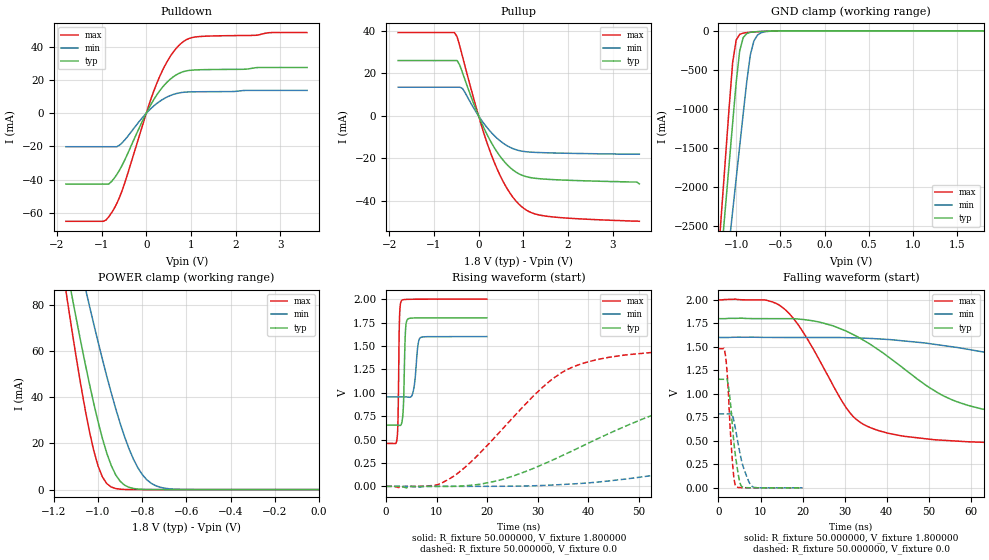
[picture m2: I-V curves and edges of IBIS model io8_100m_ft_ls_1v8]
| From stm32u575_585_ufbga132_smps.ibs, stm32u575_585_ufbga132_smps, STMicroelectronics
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|   Model io8_100m_ft_ls_1v8
[Model]  io8_100m_ft_ls_1v8
Model_type I/O
Polarity   Non-Inverting
Enable   Active-Low
Vinl =   0.540000V
Vinh =   1.260000V
Vmeas =  0.900000V
Cref =   50.000000pF
Rref =   100.000000M
Vref =   0.0V
C_comp   3.148300pF   3.147400pF   3.196500pF
[Temperature Range]   25.000000   0.140000k   -40.000000
[Pullup Reference]   1.800000V   1.600000V   2.000000V
[Pulldown Reference]   0.0V   0.0V   0.0V
[POWER Clamp Reference]   1.800000V   1.600000V   2.000000V
[GND Clamp Reference]   0.0V   0.0V   0.0V
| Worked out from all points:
|   slope of the pulldown table from 0 to 0.27 V, typ, clamps not added: 21.7 ohm
|   slope of the pullup table from 0 to 0.27 V, typ, clamps not added: 22.6 ohm
|   GND clamp passes 1 mA (typ) near -0.51 V on its own axis
|   POWER clamp passes 1 mA (typ) near -0.86 V on its own axis
|   rising waveform, R_fixture 50.000000, V_fixture 1.800000: 20-80 % time 318ps typ, 624ps min, 230ps max; typ from 0.654 V to 1.8 V
|   rising waveform, R_fixture 50.000000, V_fixture 0.0: 20-80 % time 31.3ns typ, 66.8ns min, 16.5ns max; typ from 0 V to 1.16 V
|   falling waveform, R_fixture 50.000000, V_fixture 1.800000: 20-80 % time 24.5ns typ, 55.4ns min, 12.3ns max; typ from 1.8 V to 0.654 V
|   falling waveform, R_fixture 50.000000, V_fixture 0.0: 20-80 % time 1.6ns typ, 2.38ns min, 1.18ns max; typ from 1.16 V to 0 V
[Pulldown]
|Voltage   I(typ)   I(min)   I(max)
-1.8V     -42.74mA   -20.21mA   -65.25mA
-960mV    -42.74mA   -20.21mA   -65.25mA
-780mV    -41.3mA    -20.21mA   -60.25mA
-660mV    -37mA      -20.2mA    -54.5mA
-540mV    -31.39mA   -17.82mA   -46.65mA
0V        0A         0A         10fA
240mV     11.28mA    6.002mA    18.38mA
480mV     19.18mA    10.02mA    31.83mA
780mV     24.67mA    12.5mA     42.21mA
960mV     25.9mA     12.9mA     45.21mA
1.2V      26.29mA    13.01mA    46.37mA
3.6V      27.67mA    13.81mA    48.75mA
[Pullup]
|Voltage   I(typ)   I(min)   I(max)
-1.8V     26.06mA    13.5mA     39.23mA
-540mV    26.06mA    13.5mA     39.23mA
-480mV    26.06mA    13.5mA     37.19mA
-360mV    20.34mA    12.93mA    27.94mA
0V        590fA      222pA      0A
300mV     -13.1mA    -8.158mA   -19.11mA
480mV     -18.98mA   -11.71mA   -27.97mA
660mV     -23.42mA   -14.29mA   -34.95mA
1.02V     -28.29mA   -16.75mA   -43.65mA
1.26V     -29.33mA   -17.15mA   -46.11mA
1.62V     -29.92mA   -17.41mA   -47.45mA
3.6V      -32mA      -18mA      -49.6mA
[GND_clamp]
|Voltage   I(typ)   I(min)   I(max)
-1.8V     -9.707A    -9.942A    -9.774A
-1.2V     -3.309A    -4.006A    -2.864A
-1.16V    -2.777A    -3.584A    -2.239A
-1.12V    -2.246A    -3.162A    -1.614A
-1.04V    -1.186A    -2.319A    -408.6mA
-1V       -663.9mA   -1.898A    -117.8mA
-960mV    -254mA     -1.478A    -45.14mA
-920mV    -86.03mA   -1.06A     -28.58mA
-840mV    -19.12mA   -308.9mA   -18.74mA
-800mV    -13.39mA   -130.8mA   -15.31mA
-720mV    -7.948mA   -25.37mA   -9.381mA
1.8V      0A         14.97nA    0A
[POWER_clamp]
|Voltage   I(typ)   I(min)   I(max)
-1.8V     470.8mA    433.7mA    554.6mA
-1.14V    95.25mA    122.7mA    82.82mA
-1.12V    84.97mA    114mA      70.27mA
-1.06V    55.51mA    88.42mA    35.67mA
-1.04V    46.34mA    80.15mA    25.76mA
-1V       29.51mA    64.13mA    10.3mA
-940mV    10.39mA    41.86mA    1.109mA
-900mV    3.624mA    28.77mA    182.8uA
-840mV    490.7uA    13.24mA    11.35uA
-800mV    116.8uA    6.532mA    1.77uA
-740mV    13.2uA     1.723mA    109.3nA
0V        0A         18.72nA    0A
[Ramp]
| variable   typ   min   max
dV/dt_r  0.69300/31.23919n   0.47203/66.66685n   0.88872/16.44284n
dV/dt_f  0.68762/24.43834n   0.38672/55.37808n   0.92481/12.23929n
R_load = 50.000000
[Rising Waveform]
R_fixture= 50.000000
V_fixture= 1.800000
V_fixture_min= 1.600000
V_fixture_max= 2.000000
|time   V(typ)   V(min)   V(max)
0s        654mV      955.4mV    458.7mV
2.202ns   653.9mV    955.4mV    531.7mV
2.362ns   653.5mV    955.4mV    755.5mV
2.643ns   651.3mV    955.4mV    1.796V
3.043ns   670.5mV    955.4mV    1.984V
3.443ns   892.7mV    955.4mV    1.995V
3.844ns   1.677V     955.2mV    1.997V
4.244ns   1.785V     953.9mV    1.997V
6.807ns   1.8V       1.589V     1.999V
19.94ns   1.8V       1.6V       2V
[Rising Waveform]
R_fixture= 50.000000
V_fixture= 0.0
V_fixture_min= 0.0
V_fixture_max= 0.0
|time   V(typ)   V(min)   V(max)
0s        2.236nV    145.8nV    1.532nV
9.61ns    -283.2uV   -156uV     10.23mV
13.61ns   913.9uV    -131.1uV   117.1mV
23.22ns   77.29mV    902.9uV    623.5mV
36.04ns   357.9mV    23.08mV    1.252V
53.65ns   779.1mV    122.5mV    1.435V
68.87ns   1.001V     250mV      1.467V
82.48ns   1.082V     366.7mV    1.476V
153ns     1.152V     714.2mV    1.481V
398.8ns   1.155V     786.8mV    1.481V
[Falling Waveform]
R_fixture= 50.000000
V_fixture= 1.800000
V_fixture_min= 1.600000
V_fixture_max= 2.000000
|time   V(typ)   V(min)   V(max)
0s        1.8V       1.6V       2V
14.41ns   1.8V       1.6V       1.946V
19.22ns   1.795V     1.6V       1.718V
32.83ns   1.613V     1.595V     726.8mV
51.25ns   1.037V     1.528V     512.7mV
59.26ns   878.7mV    1.475V     490.5mV
75.28ns   754.3mV    1.33V      471.6mV
100.1ns   690.3mV    1.142V     461.7mV
140.9ns   662.5mV    1.026V     458.9mV
398.8ns   654mV      955.4mV    458.7mV
[Falling Waveform]
R_fixture= 50.000000
V_fixture= 0.0
V_fixture_min= 0.0
V_fixture_max= 0.0
|time   V(typ)   V(min)   V(max)
0s        1.155V     786.8mV    1.481V
1.281ns   1.155V     786.8mV    1.486V
1.682ns   1.155V     786.8mV    1.4V
2.402ns   1.067V     786.6mV    972.1mV
2.803ns   920.7mV    788.5mV    617.4mV
3.363ns   633.2mV    767.6mV    251.8mV
4.124ns   313.2mV    607.2mV    19.01mV
5.285ns   31.68mV    329.3mV    2.175mV
7.888ns   730.9uV    20.12mV    461.8uV
19.94ns   2.236nV    145.8nV    1.532nV
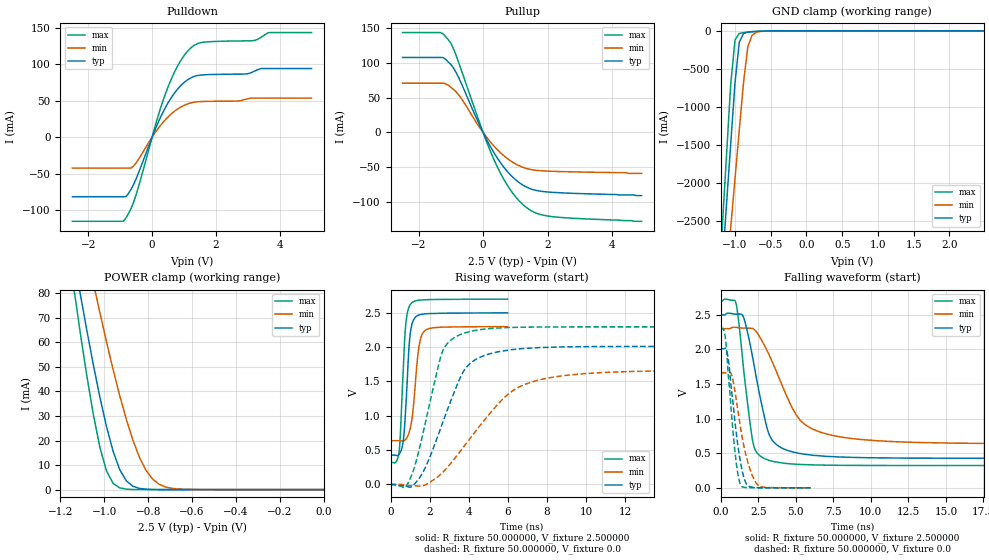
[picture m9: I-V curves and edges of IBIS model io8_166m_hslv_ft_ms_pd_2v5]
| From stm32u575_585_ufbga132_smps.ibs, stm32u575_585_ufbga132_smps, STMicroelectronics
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|   Model io8_166m_hslv_ft_ms_pd_2v5
[Model]  io8_166m_hslv_ft_ms_pd_2v5
Model_type I/O
Polarity   Non-Inverting
Enable   Active-Low
Vinl =   0.750000V
Vinh =   1.750000V
Vmeas =  1.250000V
Cref =   50.000000pF
Rref =   100.000000M
Vref =   0.0V
C_comp   3.458600pF   3.458000pF   3.495600pF
[Temperature Range]   25.000000   0.140000k   -40.000000
[Pullup Reference]   2.500000V   2.300000V   2.700000V
[Pulldown Reference]   0.0V   0.0V   0.0V
[POWER Clamp Reference]   2.500000V   2.300000V   2.700000V
[GND Clamp Reference]   0.0V   0.0V   0.0V
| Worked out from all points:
|   slope of the pulldown table from 0 to 0.375 V, typ, clamps not added: 10.1 ohm
|   slope of the pullup table from 0 to 0.375 V, typ, clamps not added: 11.7 ohm
|   GND clamp passes 1 mA (typ) near -0.50 V on its own axis
|   POWER clamp passes 1 mA (typ) near -0.86 V on its own axis
|   rising waveform, R_fixture 50.000000, V_fixture 2.500000: 20-80 % time 251ps typ, 332ps min, 235ps max; typ from 0.427 V to 2.5 V
|   rising waveform, R_fixture 50.000000, V_fixture 0.0: 20-80 % time 1.64ns typ, 2.93ns min, 1.12ns max; typ from 0 V to 2.01 V
|   falling waveform, R_fixture 50.000000, V_fixture 2.500000: 20-80 % time 1.17ns typ, 2.21ns min, 751ps max; typ from 2.5 V to 0.427 V
|   falling waveform, R_fixture 50.000000, V_fixture 0.0: 20-80 % time 664ps typ, 865ps min, 542ps max; typ from 2.01 V to 0 V
[Pulldown]
|Voltage   I(typ)   I(min)   I(max)
-2.5V     -81.61mA   -42.31mA   -115.3mA
-900mV    -81.61mA   -42.31mA   -115.3mA
-820mV    -81.43mA   -42.31mA   -110.6mA
-500mV    -56.95mA   -35.08mA   -78.57mA
140mV     15.18mA    9.02mA     22.02mA
460mV     44mA       25.98mA    64.38mA
860mV     68.91mA    40.27mA    102.2mA
1.26V     82.21mA    47.42mA    124mA
1.66V     85.54mA    49mA       130.3mA
3.18V     89.84mA    53.64mA    132.3mA
3.66V     94.01mA    53.64mA    143.3mA
5V        94.01mA    53.64mA    143.3mA
[Pullup]
|Voltage   I(typ)   I(min)   I(max)
-2.5V     108.1mA    71mA       143.9mA
-1.32V    108.1mA    71mA       143.9mA
-1.16V    105.3mA    70.2mA     137.9mA
-1V       97.96mA    65.11mA    128.6mA
-680mV    71.17mA    49.12mA    90.46mA
-40mV     3.893mA    2.628mA    5.181mA
360mV     -30.97mA   -20.78mA   -41.56mA
840mV     -60.71mA   -40.52mA   -82.21mA
1.32V     -78.06mA   -51.54mA   -107.3mA
1.64V     -83.42mA   -54.54mA   -116.1mA
2.12V     -86.16mA   -55.91mA   -121.1mA
4.92V     -91mA      -59mA      -128mA
[GND_clamp]
|Voltage   I(typ)   I(min)   I(max)
-2.5V     -9.641A    -9.693A    -9.352A
-1.18V    -3.114A    -3.874A    -2.614A
-1.12V    -2.301A    -3.23A     -1.656A
-1.06V    -1.489A    -2.587A    -706.2mA
-1V       -685.8mA   -1.945A    -119.3mA
-940mV    -149.8mA   -1.304A    -34.74mA
-880mV    -35.55mA   -672.6mA   -23.08mA
-820mV    -16.21mA   -206.4mA   -17.29mA
-760mV    -10.59mA   -57.56mA   -12.42mA
-700mV    -7.163mA   -18.75mA   -8.254mA
-400mV    -112.4uA   -385.2uA   -53.47uA
2.48V     63.1uA     48.03uA    77.39uA
[POWER_clamp]
|Voltage   I(typ)   I(min)   I(max)
-2.49V    881mA      773.1mA    1.07A
-1.14V    95.25mA    122.7mA    82.82mA
-1.11V    79.9mA     109.7mA    64.14mA
-1.05V    50.87mA    84.26mA    30.57mA
-1.02V    37.63mA    72.04mA    17.17mA
-990mV    25.71mA    60.25mA    7.621mA
-930mV    8.217mA    38.43mA    713.9uA
-900mV    3.624mA    28.77mA    182.8uA
-840mV    490.7uA    13.24mA    11.35uA
-780mV    56.55uA    4.324mA    699nA
-660mV    716.7nA    226uA      9.784nA
0V        0A         19.53nA    0A
[Ramp]
| variable   typ   min   max
dV/dt_r  1.20630/1.63876n   0.99744/2.92997n   1.37748/1.11984n
dV/dt_f  1.24322/1.16710n   0.99689/2.20738n   1.42606/0.74961n
R_load = 50.000000
[Rising Waveform]
R_fixture= 50.000000
V_fixture= 2.500000
V_fixture_min= 2.300000
V_fixture_max= 2.700000
|time   V(typ)   V(min)   V(max)
0s        427.4mV    637.3mV    322.7mV
432.4ps   436.9mV    637.3mV    472mV
492.5ps   464.7mV    636.8mV    688.2mV
636.6ps   611.7mV    633.4mV    1.603V
792.8ps   1.201V     663.7mV    2.374V
924.9ps   1.922V     739.9mV    2.57V
1.021ns   2.228V     834.8mV    2.626V
1.429ns   2.466V     1.96V      2.684V
1.73ns    2.484V     2.234V     2.69V
5.982ns   2.499V     2.299V     2.7V
[Rising Waveform]
R_fixture= 50.000000
V_fixture= 0.0
V_fixture_min= 0.0
V_fixture_max= 0.0
|time   V(typ)   V(min)   V(max)
0s        -51.81uV   -11.87uV   11.8uV
800.8ps   -25.5mV    -13.53mV   -23.54mV
1.151ns   -13.84mV   -17.86mV   192.1mV
1.552ns   127.4mV    -23.34mV   613.3mV
2.653ns   891mV      172.7mV    1.935V
3.804ns   1.681V     572.7mV    2.208V
4.605ns   1.856V     869.2mV    2.256V
6.006ns   1.956V     1.313V     2.286V
8.158ns   1.998V     1.556V     2.294V
24.92ns   2.011V     1.663V     2.295V
[Falling Waveform]
R_fixture= 50.000000
V_fixture= 2.500000
V_fixture_min= 2.300000
V_fixture_max= 2.700000
|time   V(typ)   V(min)   V(max)
0s        2.499V     2.299V     2.7V
1.001ns   2.51V      2.319V     2.683V
1.502ns   2.476V     2.308V     1.764V
2.152ns   1.856V     2.298V     651.9mV
2.953ns   983.4mV    2.04V      419.1mV
3.554ns   657mV      1.76V      378.2mV
5.055ns   506.5mV    1.045V     341.1mV
6.757ns   459.8mV    796.5mV    329mV
11.71ns   431.1mV    665.8mV    323.1mV
24.92ns   427.4mV    637.3mV    322.7mV
[Falling Waveform]
R_fixture= 50.000000
V_fixture= 0.0
V_fixture_min= 0.0
V_fixture_max= 0.0
|time   V(typ)   V(min)   V(max)
0s        2.011V     1.663V     2.295V
288.3ps   2.017V     1.663V     2.197V
468.5ps   1.91V      1.663V     1.742V
720.7ps   1.404V     1.635V     1.064V
961ps     933.1mV    1.378V     500.7mV
1.153ns   600mV      1.107V     188.3mV
1.333ns   354.9mV    851mV      42.96mV
1.73ns    53.49mV    432.4mV    4.157mV
2.486ns   3.296mV    40.56mV    1.552mV
5.982ns   -51.81uV   -11.87uV   11.8uV
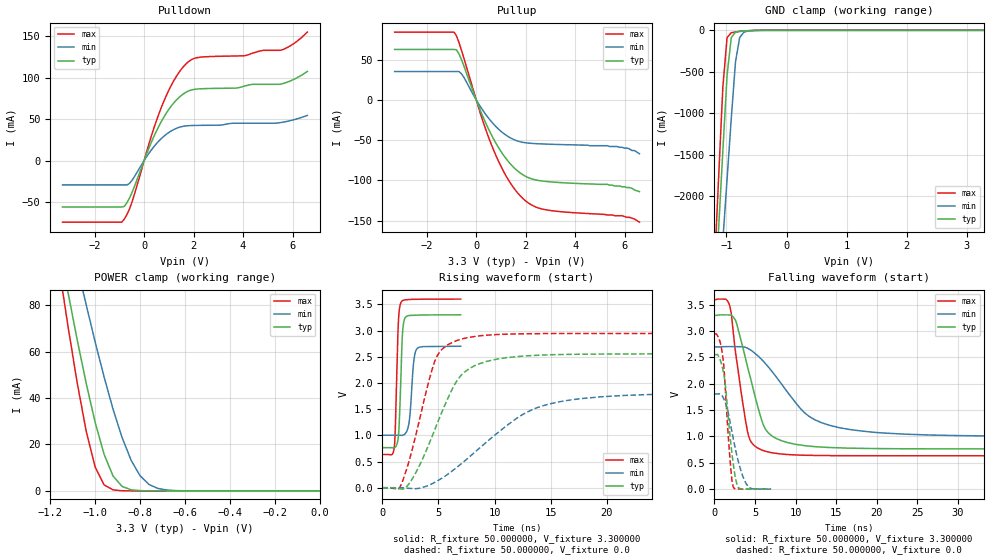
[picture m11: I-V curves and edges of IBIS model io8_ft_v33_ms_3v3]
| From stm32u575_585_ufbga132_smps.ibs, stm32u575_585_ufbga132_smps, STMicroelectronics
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|   Model io8_ft_v33_ms_3v3
[Model]  io8_ft_v33_ms_3v3
Model_type I/O
Polarity   Non-Inverting
Enable   Active-Low
Vinl =   0.990000V
Vinh =   2.310000V
Vmeas =  1.650000V
Cref =   50.000000pF
Rref =   100.000000M
Vref =   0.0V
C_comp   3.252200pF   3.221000pF   3.293600pF
[Temperature Range]   25.000000   0.140000k   -40.000000
[Pullup Reference]   3.300000V   2.700000V   3.600000V
[Pulldown Reference]   0.0V   0.0V   0.0V
[POWER Clamp Reference]   3.300000V   2.700000V   3.600000V
[GND Clamp Reference]   0.0V   0.0V   0.0V
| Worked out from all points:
|   slope of the pulldown table from 0 to 0.495 V, typ, clamps not added: 14 ohm
|   slope of the pullup table from 0 to 0.495 V, typ, clamps not added: 13.7 ohm
|   GND clamp passes 1 mA (typ) near -0.51 V on its own axis
|   POWER clamp passes 1 mA (typ) near -0.85 V on its own axis
|   rising waveform, R_fixture 50.000000, V_fixture 3.300000: 20-80 % time 246ps typ, 338ps min, 230ps max; typ from 0.764 V to 3.3 V
|   rising waveform, R_fixture 50.000000, V_fixture 0.0: 20-80 % time 3.15ns typ, 6.46ns min, 2.09ns max; typ from 0 V to 2.55 V
|   falling waveform, R_fixture 50.000000, V_fixture 3.300000: 20-80 % time 2.58ns typ, 5.68ns min, 1.62ns max; typ from 3.3 V to 0.764 V
|   falling waveform, R_fixture 50.000000, V_fixture 0.0: 20-80 % time 1ns typ, 1.54ns min, 765ps max; typ from 2.55 V to 0 V
[Pulldown]
|Voltage   I(typ)   I(min)   I(max)
-3.3V     -56.06mA   -29.42mA   -74.35mA
-900mV    -56.06mA   -29.42mA   -74.35mA
-700mV    -51.09mA   -29.42mA   -65.48mA
-500mV    -39.32mA   -24.2mA    -50.88mA
300mV     22.62mA    13.13mA    30.43mA
800mV     52.54mA    29.36mA    71.75mA
1.3V      72.91mA    38.82mA    101.4mA
1.8V      84.02mA    42.13mA    119.4mA
2.2V      86.43mA    42.46mA    124.5mA
5.5V      92.01mA    45.75mA    133mA
6.1V      98.6mA     49.6mA     142.1mA
6.6V      107.5mA    54.5mA     155mA
[Pullup]
|Voltage   I(typ)   I(min)   I(max)
-3.3V     62.6mA     35.14mA    84.13mA
-900mV    62.6mA     35.14mA    84.13mA
-800mV    62.12mA    35.14mA    79.56mA
-600mV    50.26mA    32.47mA    61.94mA
200mV     -15.65mA   -9.933mA   -19.95mA
700mV     -48.51mA   -30.11mA   -62.22mA
1.3V      -76.68mA   -45.83mA   -99.4mA
2V        -95.1mA    -53.38mA   -125.6mA
2.9V      -101.6mA   -55.08mA   -137mA
5.7V      -107mA     -58mA      -144mA
6.2V      -109mA     -61mA      -146mA
6.6V      -114mA     -67mA      -152mA
[GND_clamp]
|Voltage   I(typ)   I(min)   I(max)
-3.3V     -9.848A    -9.957A    -9.458A
-1.2V     -3.312A    -4.013A    -2.863A
-1.13V    -2.381A    -3.274A    -1.769A
-1.06V    -1.452A    -2.535A    -684.7mA
-990mV    -542.9mA   -1.798A    -88.02mA
-920mV    -87.11mA   -1.064A    -28.44mA
-850mV    -22.1mA    -382.4mA   -19.61mA
-780mV    -11.97mA   -86.98mA   -13.71mA
-710mV    -7.619mA   -22.26mA   -8.745mA
-640mV    -4.493mA   -7.773mA   -4.817mA
-360mV    -31.22uA   -172.6uA   -8.607uA
3.28V     0A         15.66nA    -5.841nA
[POWER_clamp]
|Voltage   I(typ)   I(min)   I(max)
-3.28V    1.355A     1.167A     1.664A
-1.16V    105.7mA    131.6mA    95.69mA
-1.12V    84.97mA    114mA      70.27mA
-1.08V    65.05mA    96.83mA    46.54mA
-1.04V    46.34mA    80.15mA    25.76mA
-1V       29.51mA    64.13mA    10.3mA
-960mV    15.69mA    48.99mA    2.571mA
-920mV    6.373mA    35.1mA     455.6uA
-840mV    490.7uA    13.24mA    11.36uA
-760mV    27.33uA    2.767mA    276.6nA
-640mV    346.6nA    134.1uA    15.48nA
0V        0A         19.91nA    0A
[Ramp]
| variable   typ   min   max
dV/dt_r  1.53252/3.14996n   1.08420/6.45603n   1.76664/2.08882n
dV/dt_f  1.52149/2.57428n   1.01766/5.67760n   1.77964/1.61540n
R_load = 50.000000
[Rising Waveform]
R_fixture= 50.000000
V_fixture= 3.300000
V_fixture_min= 2.700000
V_fixture_max= 3.600000
|time   V(typ)   V(min)   V(max)
0s        764.2mV    1.002V     634mV
1.065ns   764.2mV    1.002V     779.4mV
1.415ns   963.2mV    1.001V     3.103V
1.654ns   2.111V     999.2mV    3.533V
1.78ns    2.891V     1.001V     3.567V
1.948ns   3.197V     1.014V     3.581V
2.396ns   3.286V     1.271V     3.591V
2.775ns   3.29V      2.366V     3.595V
3.041ns   3.293V     2.639V     3.596V
6.979ns   3.3V       2.7V       3.6V
[Rising Waveform]
R_fixture= 50.000000
V_fixture= 0.0
V_fixture_min= 0.0
V_fixture_max= 0.0
|time   V(typ)   V(min)   V(max)
0s        35.19uV    27.9uV     37.98uV
1.441ns   -15.23mV   197.2uV    -23.32mV
2.432ns   92.1mV     -12.3mV    549.3mV
4.685ns   1.116V     105.3mV    2.421V
5.405ns   1.495V     194.8mV    2.66V
6.847ns   2.102V     425.2mV    2.823V
8.649ns   2.366V     755.2mV    2.898V
12.52ns   2.512V     1.4V       2.937V
16.04ns   2.542V     1.65V      2.943V
44.86ns   2.554V     1.807V     2.944V
[Falling Waveform]
R_fixture= 50.000000
V_fixture= 3.300000
V_fixture_min= 2.700000
V_fixture_max= 3.600000
|time   V(typ)   V(min)   V(max)
0s        3.3V       2.7V       3.6V
1.892ns   3.307V     2.706V     3.477V
2.703ns   3.159V     2.705V     2.478V
4.144ns   2.281V     2.67V      1.051V
5.766ns   1.336V     2.47V      746.5mV
6.577ns   1.081V     2.332V     708.5mV
8.108ns   929mV      2.03V      669.4mV
11.26ns   823.2mV    1.43V      643.4mV
14.23ns   790.7mV    1.21V      637.2mV
44.86ns   764.2mV    1.002V     634mV
[Falling Waveform]
R_fixture= 50.000000
V_fixture= 0.0
V_fixture_min= 0.0
V_fixture_max= 0.0
|time   V(typ)   V(min)   V(max)
0s        2.554V     1.807V     2.944V
560.6ps   2.507V     1.809V     2.856V
1.037ns   2.27V      1.749V     2.502V
1.345ns   1.972V     1.642V     1.896V
1.906ns   1.035V     1.292V     591.5mV
2.144ns   696.1mV    1.097V     189.7mV
2.298ns   504.5mV    975.5mV    55.97mV
2.817ns   69.45mV    603.9mV    3.243mV
3.924ns   2.088mV    98.93mV    961uV
6.979ns   35.19uV    27.9uV     37.98uV
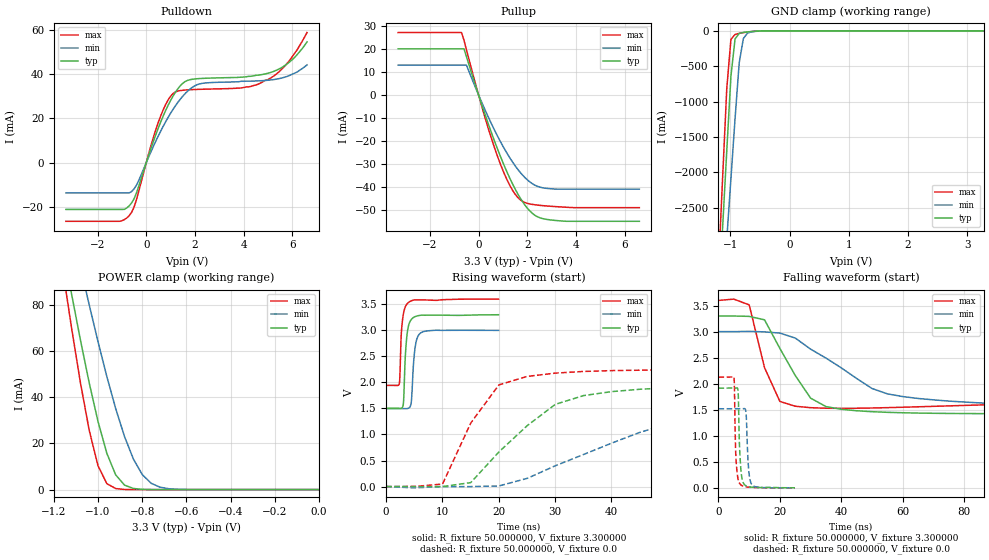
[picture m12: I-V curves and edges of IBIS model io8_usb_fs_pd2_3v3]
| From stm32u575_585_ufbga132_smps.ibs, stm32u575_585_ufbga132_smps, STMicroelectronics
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|   Model io8_usb_fs_pd2_3v3
[Model]  io8_usb_fs_pd2_3v3
Model_type I/O
Polarity   Non-Inverting
Enable   Active-Low
Vinl =   0.990000V
Vinh =   2.310000V
Vmeas =  1.650000V
Cref =   50.000000pF
Rref =   100.000000M
Vref =   0.0V
C_comp   7.156600pF   7.055100pF   7.302500pF
[Temperature Range]   25.000000   0.140000k   -40.000000
[Pullup Reference]   3.300000V   3.000000V   3.600000V
[Pulldown Reference]   0.0V   0.0V   0.0V
[POWER Clamp Reference]   3.300000V   3.000000V   3.600000V
[GND Clamp Reference]   0.0V   0.0V   0.0V
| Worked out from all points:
|   slope of the pulldown table from 0 to 0.495 V, typ, clamps not added: 31.6 ohm
|   slope of the pullup table from 0 to 0.495 V, typ, clamps not added: 32.2 ohm
|   GND clamp passes 1 mA (typ) near -0.45 V on its own axis
|   POWER clamp passes 1 mA (typ) near -0.85 V on its own axis
|   rising waveform, R_fixture 50.000000, V_fixture 3.300000: 20-80 % time 553ps typ, 603ps min, 506ps max; typ from 1.5 V to 3.3 V
|   rising waveform, R_fixture 50.000000, V_fixture 0.0: 20-80 % time 11.8ns typ, 22.7ns min, 6.67ns max; typ from 0 V to 1.91 V
|   falling waveform, R_fixture 50.000000, V_fixture 3.300000: 20-80 % time 10.8ns typ, 26.5ns min, 4.24ns max; typ from 3.3 V to 1.5 V
|   falling waveform, R_fixture 50.000000, V_fixture 0.0: 20-80 % time 698ps typ, 744ps min, 595ps max; typ from 1.91 V to 0 V
[Pulldown]
|Voltage   I(typ)   I(min)   I(max)
-3.3V     -21.13mA   -13.67mA   -26.5mA
-1.1V     -21.13mA   -13.67mA   -26.5mA
-700mV    -19.5mA    -13.67mA   -23.97mA
-500mV    -16.29mA   -11.84mA   -20.07mA
300mV     9.849mA    7.552mA    11.7mA
700mV     21.21mA    16.54mA    24.01mA
1.1V      30.11mA    24.11mA    31.23mA
1.6V      36.68mA    31.26mA    32.83mA
2.3V      38.08mA    35.84mA    33.18mA
5V        40.42mA    37.26mA    37.58mA
5.8V      44.78mA    39.04mA    45.09mA
6.6V      54.6mA     44.2mA     58.8mA
[Pullup]
|Voltage   I(typ)   I(min)   I(max)
-3.3V     19.93mA    12.9mA     26.97mA
-700mV    19.93mA    12.9mA     26.97mA
-600mV    19.93mA    12.9mA     23.65mA
-500mV    16.63mA    12.9mA     19.61mA
200mV     -6.451mA   -4.944mA   -7.53mA
700mV     -21.29mA   -16.22mA   -24.29mA
1.2V      -34.18mA   -25.84mA   -37.47mA
1.5V      -40.71mA   -30.66mA   -42.94mA
1.7V      -44.46mA   -33.41mA   -45.28mA
2.2V      -51.19mA   -38.38mA   -47.37mA
2.7V      -53.69mA   -40.32mA   -47.97mA
6.6V      -54.69mA   -40.78mA   -48.78mA
[GND_clamp]
|Voltage   I(typ)   I(min)   I(max)
-3.3V     -9.287A    -9.833A    -9.745A
-1.2V     -3.857A    -4.664A    -3.345A
-1.13V    -2.774A    -3.805A    -2.072A
-1.06V    -1.695A    -2.947A    -813.1mA
-990mV    -641.8mA   -2.091A    -120.9mA
-920mV    -113.3mA   -1.238A    -49.91mA
-850mV    -36.82mA   -452mA     -36.33mA
-780mV    -22.67mA   -108.9mA   -26.24mA
-710mV    -15.24mA   -32.28mA   -17.46mA
-570mV    -5.138mA   -7.046mA   -4.93mA
-360mV    -107.9uA   -475uA     -47.23uA
3.28V     163.3uA    123.6uA    195.4uA
[POWER_clamp]
|Voltage   I(typ)   I(min)   I(max)
-3.28V    1.355A     1.167A     1.664A
-1.16V    105.7mA    131.6mA    95.69mA
-1.12V    84.97mA    114mA      70.27mA
-1.08V    65.05mA    96.83mA    46.54mA
-1.04V    46.34mA    80.15mA    25.76mA
-1V       29.51mA    64.13mA    10.3mA
-960mV    15.69mA    48.99mA    2.571mA
-920mV    6.373mA    35.1mA     455.6uA
-840mV    490.7uA    13.24mA    11.36uA
-760mV    27.33uA    2.767mA    754.7nA
-640mV    348.1nA    134.1uA    754.7nA
0V        0A         50.53nA    0A
[Ramp]
| variable   typ   min   max
dV/dt_r  1.14882/11.44200n   0.91026/22.61236n   1.27644/5.89934n
dV/dt_f  1.07790/10.04020n   0.90108/26.35827n   0.99348/3.83611n
R_load = 50.000000
[Rising Waveform]
R_fixture= 50.000000
V_fixture= 3.300000
V_fixture_min= 3.000000
V_fixture_max= 3.600000
|time   V(typ)   V(min)   V(max)
0s        1.502V     1.496V     1.942V
2.322ns   1.501V     1.496V     1.97V
2.683ns   1.503V     1.496V     2.925V
2.963ns   1.539V     1.496V     3.245V
3.684ns   2.894V     1.496V     3.501V
4.404ns   3.198V     1.582V     3.562V
4.725ns   3.235V     2.117V     3.575V
5.285ns   3.268V     2.761V     3.583V
6.286ns   3.291V     2.959V     3.583V
19.94ns   3.298V     2.998V     3.598V
[Rising Waveform]
R_fixture= 50.000000
V_fixture= 0.0
V_fixture_min= 0.0
V_fixture_max= 0.0
|time   V(typ)   V(min)   V(max)
0s        53.31nV    535.7nV    167.2nV
10.01ns   -602.9uV   -194.3uV   47.94mV
15.02ns   75.79mV    -368.7uV   1.219V
20.02ns   664.8mV    11.46mV    1.952V
30.03ns   1.578V     399mV      2.177V
45.05ns   1.868V     1.04V      2.233V
55.06ns   1.914V     1.29V      2.239V
70.07ns   1.939V     1.411V     2.24V
145.1ns   1.948V     1.51V      2.232V
2.492us   1.913V     1.517V     2.123V
[Falling Waveform]
R_fixture= 50.000000
V_fixture= 3.300000
V_fixture_min= 3.000000
V_fixture_max= 3.600000
|time   V(typ)   V(min)   V(max)
0s        3.298V     2.998V     3.598V
10.01ns   3.291V     3.003V     3.512V
15.02ns   3.225V     2.993V     2.305V
20.02ns   2.675V     2.97V      1.657V
30.03ns   1.721V     2.662V     1.537V
35.04ns   1.559V     2.491V     1.527V
50.05ns   1.461V     1.907V     1.532V
65.07ns   1.434V     1.715V     1.555V
175.2ns   1.439V     1.517V     1.718V
2.492us   1.502V     1.496V     1.942V
[Falling Waveform]
R_fixture= 50.000000
V_fixture= 0.0
V_fixture_min= 0.0
V_fixture_max= 0.0
|time   V(typ)   V(min)   V(max)
0s        1.913V     1.517V     2.123V
5.005ns   1.915V     1.517V     2.124V
5.706ns   1.915V     1.518V     551.3mV
6.406ns   1.834V     1.519V     161.5mV
6.907ns   724.7mV    1.519V     82.08mV
7.608ns   195.9mV    1.519V     42.56mV
8.909ns   40.94mV    1.469V     17.32mV
9.81ns    21.69mV    373.6mV    11.16mV
10.81ns   11.73mV    65.83mV    8.33mV
24.92ns   53.31nV    535.7nV    167.2nV
